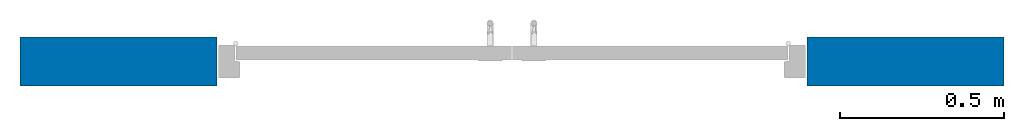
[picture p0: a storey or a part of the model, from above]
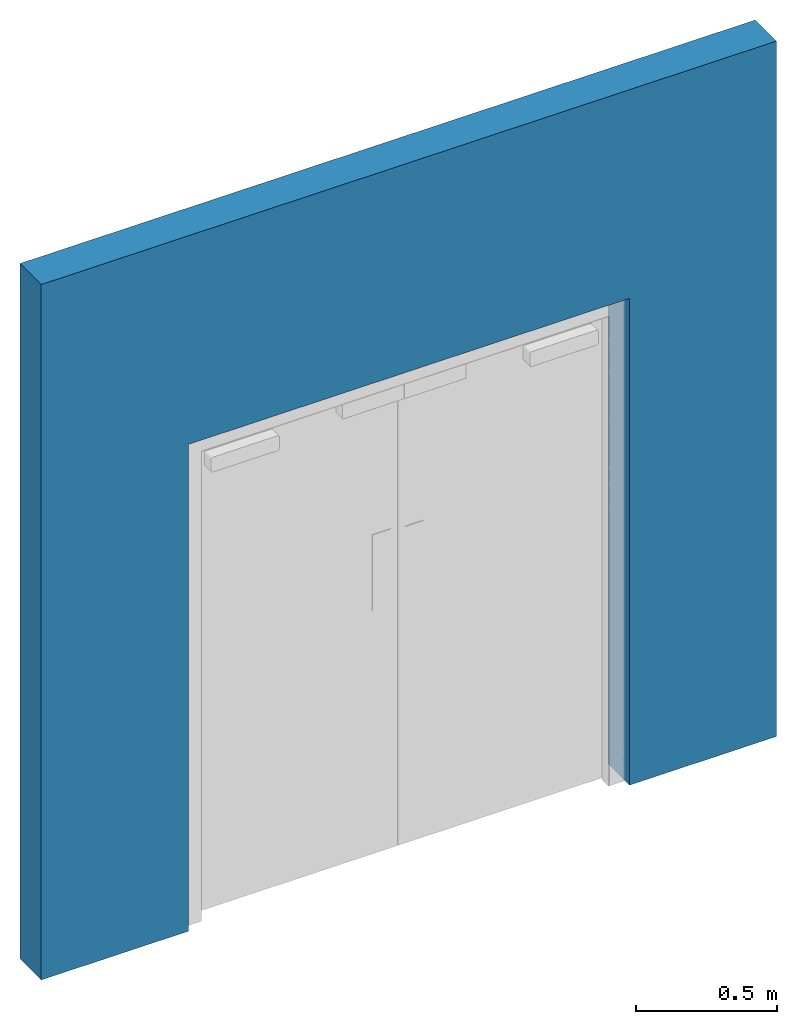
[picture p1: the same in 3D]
Properties of the parts of a building model (IFC2X3)

# File
Description: ViewDefinition [CoordinationView_V2.0]
Time: 2015-03-31T14:15:35
Written by: The EXPRESS Data Manager Version 5.01.0100.02.64mod : 6 Jun 2012
Made in: 20130709_2115(x64) - Exporter 3.12.0.0 - Alternate UI 2.12.0.0
Comment: STEP Physical File produced by: The EXPRESS Data Manager Version 5.01.0100.02.64mod : 6 Jun 2012 * Module: EDMstepFileFactory/EDMstandAlone * Creation date: Tue Mar 31 14:15:35 2015 * Host: NCL-TA29 * Database: C:\Users\Vickersc\AppData\Local\Temp\{30B55171-51F5-4646-841A-365A6D0FF748}\ifc * Database version: 5507 * Database creation date: Tue Mar 31 14:15:33 2015 * Schema: IFC2X3 * Model: DataRepository.ifc * Model creation date: Tue Mar 31 14:15:33 2015 * Header model: DataRepository.ifc_HeaderModel * Header model creation date: Tue Mar 31 14:15:33 2015 * EDMuser: sdai-user * EDMgroup: sdai-group * License ID and type: 5605 : Permanent license. Expiry date: * EDMstepFileFactory options: 020000

# IfcProject
LongName: X:\NBL\Manufacturer\A\Assa Abloy 0060A_8204\WIP\Xbim\Batch2\IFC\NBS_AssaAbloyLtd_DrsetSym_AASDMetalAccessControlDoor_Double.ifc

# IfcSite, Default
RefLatitude: 42, 24, 53, 508911; RefLongitude: -71, -15, -29, -58837; RefElevation: 0 mm

# IfcBuildingStorey, Level 1
LongName: Level 1; Elevation: 0 mm

# IfcDoor: 1800x2100mm, NBS_AssaAbloyLtd_DrsetSym_AASDMetalAccessControlDoor_Double:1800x2100mm:654644
In: Level 1
Type - ParameterTakesPrecedence: no; Sizeable: no; Material: NBS_Concept
Type - Pset_DoorCommon - FireExit: no; FireRating: Certifire CF520 tested up to 240 minutes (dependant on configuration); GlazingAreaFraction: 0; HandicapAccessible: yes; HasDrive: no; Infiltration: 0 m3/s; IsExternal: no; Reference: n/a; SecurityRating: Unrated; SelfClosing: yes; SmokeStop: no; ThermalTransmittance: 0 kg/K/s3
Type - COBie - AccessibilityPerformance: n/a; CodePerformance: n/a; Constituents: n/a; Features: n/a; Finish: n/a; Grade: n/a; Manufacturer: sales@assaabloy.co.uk; Material: n/a; ModelReference: AASD Metal Access Control Door; NominalHeight: 2100 mm; NominalLength: 0 mm; NominalWidth: 1800 mm; ReplacementCost: n/a; Shape: Rectangle; Size: 1800 x 2100 mm; SustainabilityPerformance: n/a; WarrantyDescription: n/a; WarrantyDurationParts: n/a; WarrantyGuarantorParts: n/a; AssetType: Fixed; Category: n/a; DurationUnit: year; Name: DoorsetSystem_AASDMetalAccessControlDoor_Double-1800x2100mm_AssaAbloyLtd; WarrantyDurationUnit: year; ExpectedLife: n/a; Description: Double metal door for access control use; Color: n/a; ModelNumber: n/a; WarrantyDurationLabor: n/a; WarrantyGuarantorLabor: n/a
Type - NBS_General - Revision: n/a; NBSOfficeMasterTag: n/a; Author: NBS; BIMObjectName: NBS_AssaAbloyLtd_DoorsetSystem_AASDMetalAccessControlDoor_Double-1800x2100mm; ManufacturerName: Assa Abloy Ltd; ManufacturerURL: www.assaabloy.co.uk; NBSCertification: www.nationalbimlibrary.com/assa-abloy/double-metal-access-control-door; NBSDescription: Doorset system; NBSNote: 25-90-20/120; NBSReference: 25-50-20/120; NBSTypeID: n/a; Uniclass2: 25-30-20/120; Version: 1; ProductInformation: www.assaabloy.co.uk/en/local/uk/About-ASSA-ABLOY/UK-organisation/Security-Doors/Products1/Powershield-Doors/
Type - NBS_Data - AirTransferGrille: no; AirTransferGrilleSize: n/a; AlternativeDoorsetGlazing: n/a; AntiFingerTrapRequirement: no; AutomaticHardware: n/a; BreakoutFacility: no; CloserOptions: Push Side (AAUK ODC002), Pull Side (AAUK ODC002), None; Configuration: Double leaf, single action; DoorSeal: no; DoorsetFasteners: AASD Bespoke frame adjusters with specialised screw fixings for masonry, timber or metal; DoorsetType: Metal; DoorstopOptions: Floor mounted door stop, Wall mounted door stop; EmergencyPanicOperation: n/a; FireRatingOptions: Unrated, 30 minutes, 60 minutes, 120 minutes, 240 minutes; FrameFinish: n/a; FrameFinishlOptions: Epoxy powder primed, Polyester powder coated, Satin polish 180-240 grit (stainless steel only), Patterned finish (stainless steel only), Laminates; FrameMaterial: n/a; FrameMaterialOptions: Steel Galvatite ZF ‘Galvanneal’, Stainless Steel Grade 304, Stainless Steel Grade 332; FrameProfileOptions: Double Rebate, Single Rebate, Split Frame; FrameRevealFiller: n/a; FrameSeal: yes; FrameWidthOptions: Available from minimum of 100 mm (Single Rebate), 146 mm (Double Rebate) and 80 mm (Split Frame); GlassType: n/a; Hanging: n/a; HardwareSetOptions: Hardware Set 1 (DT-HW-ML), Hardware Set 2 (DT-HW-SL); LeafFacingOptions: Epoxy powder primed, Polyester powder coated, Satin polish 180-240 grit (stainless steel only), Patterned finish (stainless steel only), Laminates; LeafMaterialOptions: Steel Galvatite ZF ‘Galvanneal’, Stainless Steel Grade 304, Stainless Steel Grade 316; LeafSwingOptions: Inward opening, Outward opening; LockingOptions: AAUK CDL001, AAUK ECT001, AAUK EPCE001, AAUK MEL001, AAUK MLAP001, AAUK SMML001; MaximumStructuralOpening: 2800 x 3000 mm; MinimumStructuralOpening: 1000 x 1000 mm; Operating: AAUK GDS001; OperationOptions: AASD PP002, AAUK LH003, AAUK PH002BT; OverPanels: n/a; PlatesAndStops: n/a; Securing: AASD FB001, Security contact; SecurityRatingOptions: Various security enhancements are available, please contact ASSA ABLOY Security Doors for more details; SidePanels: n/a; SignageFireOptions: AAUK FDKS001, AAUK FDKL001, None; SuitableLocation: Access control; SystemAccessories: n/a; ThermalTransmittanceOptions: 3.7 (Optional upgrade to 1.6, please contact ASSA ABLOY Security Doors for more details); ThresholdBase: n/a; ThresholdRequired: no; ThresholdStripping: no; Trim: n/a; VisionPanelConfiguration: n/a; VisionPanelOptions: Vision Panel Type 2
OverallHeight: 2100 mm; OverallWidth: 1800 mm
COBie - AssetIdentifier: n/a; BarCode: n/a; InstallationDate: 1900-12-31T23:59:59; SerialNumber: n/a; TagNumber: n/a; WarrantyStartDate: 1900-12-31T23:59:59
NBS_Data - ComponentNumber: n/a; DoorNumber: n/a; ElectronicLock: no; FloorFinish: n/a; Handing: n/a; HardwareSet: DT-HW-ML; HeadDetail: n/a; HoldOpen: no; JambDetail: n/a; KeySuiting: n/a; LeafEdgings: n/a; LeafFacing: n/a; LeafSwing: n/a; OpeningMechanism: no; SignageFire: n/a; SignageSecurity: n/a; SignageWayfinding: n/a

# IfcWallStandardCase: Basic Wall:NBS_Int_Concept, Basic Wall:NBS_Int_Concept:2301
In: Level 1
Type - PredefinedType: STANDARD; Material: nbl_Concept 150 mm
